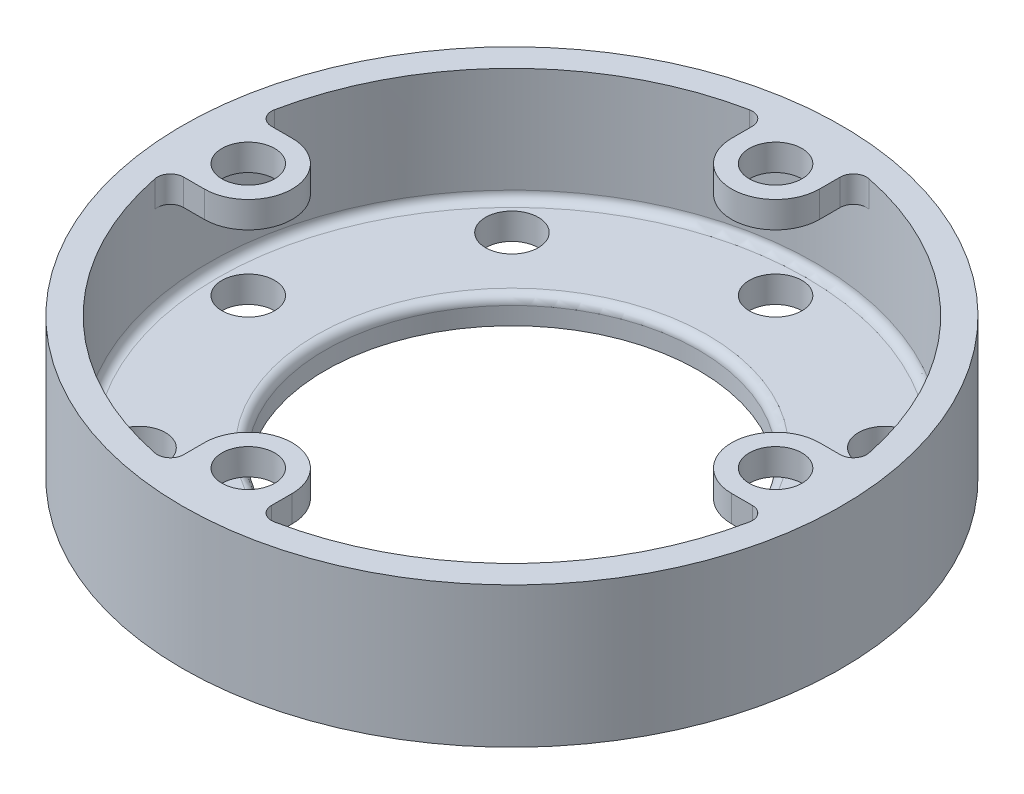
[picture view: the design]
ISO-10303-21;
HEADER;
FILE_DESCRIPTION(('STEP AP214'),'2;1');
FILE_NAME('part.step','',(''),(''),'','','');
FILE_SCHEMA(('AUTOMOTIVE_DESIGN { 1 0 10303 214 1 1 1 1 }'));
ENDSEC;
DATA;
#1=APPLICATION_CONTEXT('core data for automotive mechanical design processes');
#2=APPLICATION_PROTOCOL_DEFINITION('international standard','automotive_design',2000,#1);
#3=PRODUCT_CONTEXT('',#1,'mechanical');
#4=PRODUCT('Part','Part','',(#3));
#5=PRODUCT_RELATED_PRODUCT_CATEGORY('part','',(#4));
#6=PRODUCT_DEFINITION_FORMATION('','',#4);
#7=PRODUCT_DEFINITION_CONTEXT('part definition',#1,'design');
#8=PRODUCT_DEFINITION('design','',#6,#7);
#9=PRODUCT_DEFINITION_SHAPE('','',#8);
#10=(LENGTH_UNIT() NAMED_UNIT(*) SI_UNIT(.MILLI.,.METRE.));
#11=(NAMED_UNIT(*) PLANE_ANGLE_UNIT() SI_UNIT($,.RADIAN.));
#12=(NAMED_UNIT(*) SI_UNIT($,.STERADIAN.) SOLID_ANGLE_UNIT());
#13=UNCERTAINTY_MEASURE_WITH_UNIT(LENGTH_MEASURE(1.E-05),#10,'distance_accuracy_value','');
#14=(GEOMETRIC_REPRESENTATION_CONTEXT(3) GLOBAL_UNCERTAINTY_ASSIGNED_CONTEXT((#13)) GLOBAL_UNIT_ASSIGNED_CONTEXT((#10,
#11,#12)) REPRESENTATION_CONTEXT('',''));
#15=CARTESIAN_POINT('',(0.,0.,0.));
#16=DIRECTION('',(0.,0.,1.));
#17=DIRECTION('',(1.,0.,0.));
#18=AXIS2_PLACEMENT_3D('',#15,#16,#17);
#19=CARTESIAN_POINT('',(0.,32.,0.));
#20=DIRECTION('',(0.,-1.,0.));
#21=DIRECTION('',(0.,0.,-1.));
#22=AXIS2_PLACEMENT_3D('',#19,#20,#21);
#23=CYLINDRICAL_SURFACE('',#22,69.);
#24=CARTESIAN_POINT('',(0.,8.,0.));
#25=DIRECTION('',(0.,1.,0.));
#26=DIRECTION('',(0.,0.,1.));
#27=AXIS2_PLACEMENT_3D('',#24,#25,#26);
#28=CIRCLE('',#27,69.);
#29=CARTESIAN_POINT('',(0.,8.,69.));
#30=VERTEX_POINT('',#29);
#31=EDGE_CURVE('E11',#30,#30,#28,.F.);
#32=ORIENTED_EDGE('',*,*,#31,.T.);
#33=EDGE_LOOP('',(#32));
#34=FACE_BOUND('',#33,.T.);
#35=CARTESIAN_POINT('',(0.,32.,0.));
#36=DIRECTION('',(0.,1.,0.));
#37=DIRECTION('',(0.,0.,1.));
#38=AXIS2_PLACEMENT_3D('',#35,#36,#37);
#39=CIRCLE('',#38,69.);
#40=CARTESIAN_POINT('',(13.5909088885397,32.,67.6482608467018));
#41=VERTEX_POINT('',#40);
#42=CARTESIAN_POINT('',(67.648260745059,32.,13.5909093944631));
#43=VERTEX_POINT('',#42);
#44=EDGE_CURVE('E495',#41,#43,#39,.T.);
#45=ORIENTED_EDGE('',*,*,#44,.T.);
#46=DIRECTION('',(0.,-1.,0.));
#47=VECTOR('',#46,1.);
#48=CARTESIAN_POINT('',(67.648260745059,32.,13.5909093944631));
#49=LINE('',#48,#47);
#50=CARTESIAN_POINT('',(67.648260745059,26.,13.5909093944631));
#51=VERTEX_POINT('',#50);
#52=EDGE_CURVE('E387',#43,#51,#49,.T.);
#53=ORIENTED_EDGE('',*,*,#52,.T.);
#54=CARTESIAN_POINT('',(0.,26.,0.));
#55=DIRECTION('',(0.,1.,0.));
#56=DIRECTION('',(-1.,0.,-4.48724098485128E-09));
#57=AXIS2_PLACEMENT_3D('',#54,#55,#56);
#58=CIRCLE('',#57,69.);
#59=CARTESIAN_POINT('',(67.6482608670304,26.,-13.590908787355));
#60=VERTEX_POINT('',#59);
#61=EDGE_CURVE('E224',#51,#60,#58,.T.);
#62=ORIENTED_EDGE('',*,*,#61,.T.);
#63=DIRECTION('',(0.,-1.,0.));
#64=VECTOR('',#63,1.);
#65=CARTESIAN_POINT('',(67.6482608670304,32.,-13.590908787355));
#66=LINE('',#65,#64);
#67=CARTESIAN_POINT('',(67.6482608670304,32.,-13.590908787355));
#68=VERTEX_POINT('',#67);
#69=EDGE_CURVE('E381',#60,#68,#66,.F.);
#70=ORIENTED_EDGE('',*,*,#69,.T.);
#71=CARTESIAN_POINT('',(13.5909090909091,32.,-67.6482608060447));
#72=VERTEX_POINT('',#71);
#73=EDGE_CURVE('E307',#68,#72,#39,.T.);
#74=ORIENTED_EDGE('',*,*,#73,.T.);
#75=DIRECTION('',(0.,-1.,0.));
#76=VECTOR('',#75,1.);
#77=CARTESIAN_POINT('',(13.5909090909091,32.,-67.6482608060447));
#78=LINE('',#77,#76);
#79=CARTESIAN_POINT('',(13.5909090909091,26.,-67.6482608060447));
#80=VERTEX_POINT('',#79);
#81=EDGE_CURVE('E327',#72,#80,#78,.T.);
#82=ORIENTED_EDGE('',*,*,#81,.T.);
#83=CARTESIAN_POINT('',(0.,26.,0.));
#84=DIRECTION('',(0.,1.,0.));
#85=DIRECTION('',(0.,0.,1.));
#86=AXIS2_PLACEMENT_3D('',#83,#84,#85);
#87=CIRCLE('',#86,69.);
#88=CARTESIAN_POINT('',(-13.5909090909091,26.,-67.6482608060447));
#89=VERTEX_POINT('',#88);
#90=EDGE_CURVE('E282',#80,#89,#87,.T.);
#91=ORIENTED_EDGE('',*,*,#90,.T.);
#92=DIRECTION('',(0.,-1.,0.));
#93=VECTOR('',#92,1.);
#94=CARTESIAN_POINT('',(-13.5909090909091,32.,-67.6482608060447));
#95=LINE('',#94,#93);
#96=CARTESIAN_POINT('',(-13.5909090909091,32.,-67.6482608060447));
#97=VERTEX_POINT('',#96);
#98=EDGE_CURVE('E324',#89,#97,#95,.F.);
#99=ORIENTED_EDGE('',*,*,#98,.T.);
#100=CARTESIAN_POINT('',(-67.6482607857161,32.,-13.5909091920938));
#101=VERTEX_POINT('',#100);
#102=EDGE_CURVE('E309',#97,#101,#39,.T.);
#103=ORIENTED_EDGE('',*,*,#102,.T.);
#104=DIRECTION('',(0.,-1.,0.));
#105=VECTOR('',#104,1.);
#106=CARTESIAN_POINT('',(-67.6482607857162,32.,-13.5909091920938));
#107=LINE('',#106,#105);
#108=CARTESIAN_POINT('',(-67.6482607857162,26.,-13.5909091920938));
#109=VERTEX_POINT('',#108);
#110=EDGE_CURVE('E350',#101,#109,#107,.T.);
#111=ORIENTED_EDGE('',*,*,#110,.T.);
#112=CARTESIAN_POINT('',(0.,26.,0.));
#113=DIRECTION('',(0.,1.,0.));
#114=DIRECTION('',(1.,0.,1.49574714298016E-09));
#115=AXIS2_PLACEMENT_3D('',#112,#113,#114);
#116=CIRCLE('',#115,69.);
#117=CARTESIAN_POINT('',(-67.6482608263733,26.,13.5909089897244));
#118=VERTEX_POINT('',#117);
#119=EDGE_CURVE('E257',#109,#118,#116,.T.);
#120=ORIENTED_EDGE('',*,*,#119,.T.);
#121=DIRECTION('',(0.,-1.,0.));
#122=VECTOR('',#121,1.);
#123=CARTESIAN_POINT('',(-67.6482608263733,32.,13.5909089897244));
#124=LINE('',#123,#122);
#125=CARTESIAN_POINT('',(-67.6482608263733,32.,13.5909089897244));
#126=VERTEX_POINT('',#125);
#127=EDGE_CURVE('E343',#118,#126,#124,.F.);
#128=ORIENTED_EDGE('',*,*,#127,.T.);
#129=CARTESIAN_POINT('',(-13.5909092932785,32.,67.6482607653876));
#130=VERTEX_POINT('',#129);
#131=EDGE_CURVE('E313',#126,#130,#39,.T.);
#132=ORIENTED_EDGE('',*,*,#131,.T.);
#133=DIRECTION('',(0.,-1.,0.));
#134=VECTOR('',#133,1.);
#135=CARTESIAN_POINT('',(-13.5909092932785,32.,67.6482607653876));
#136=LINE('',#135,#134);
#137=CARTESIAN_POINT('',(-13.5909092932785,26.,67.6482607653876));
#138=VERTEX_POINT('',#137);
#139=EDGE_CURVE('E370',#130,#138,#136,.T.);
#140=ORIENTED_EDGE('',*,*,#139,.T.);
#141=CARTESIAN_POINT('',(0.,26.,0.));
#142=DIRECTION('',(0.,1.,0.));
#143=DIRECTION('',(2.99149428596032E-09,0.,-1.));
#144=AXIS2_PLACEMENT_3D('',#141,#142,#143);
#145=CIRCLE('',#144,69.);
#146=CARTESIAN_POINT('',(13.5909088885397,26.,67.6482608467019));
#147=VERTEX_POINT('',#146);
#148=EDGE_CURVE('E232',#138,#147,#145,.T.);
#149=ORIENTED_EDGE('',*,*,#148,.T.);
#150=DIRECTION('',(0.,-1.,0.));
#151=VECTOR('',#150,1.);
#152=CARTESIAN_POINT('',(13.5909088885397,32.,67.6482608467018));
#153=LINE('',#152,#151);
#154=EDGE_CURVE('E364',#147,#41,#153,.F.);
#155=ORIENTED_EDGE('',*,*,#154,.T.);
#156=EDGE_LOOP('',(#45,#53,#62,#70,#74,#82,#91,#99,#103,#111,#120,#128,#132,#140,#149,#155));
#157=FACE_BOUND('',#156,.T.);
#158=ADVANCED_FACE('F39',(#34,#157),#23,.F.);
#159=CARTESIAN_POINT('',(0.,32.,0.));
#160=DIRECTION('',(0.,-1.,0.));
#161=DIRECTION('',(0.,0.,-1.));
#162=AXIS2_PLACEMENT_3D('',#159,#160,#161);
#163=CYLINDRICAL_SURFACE('',#162,75.);
#164=CARTESIAN_POINT('',(0.,32.,0.));
#165=DIRECTION('',(0.,1.,0.));
#166=DIRECTION('',(0.,0.,1.));
#167=AXIS2_PLACEMENT_3D('',#164,#165,#166);
#168=CIRCLE('',#167,75.);
#169=CARTESIAN_POINT('',(0.,32.,75.));
#170=VERTEX_POINT('',#169);
#171=EDGE_CURVE('E314',#170,#170,#168,.T.);
#172=ORIENTED_EDGE('',*,*,#171,.F.);
#173=EDGE_LOOP('',(#172));
#174=FACE_BOUND('',#173,.T.);
#175=CARTESIAN_POINT('',(0.,0.,0.));
#176=DIRECTION('',(0.,1.,0.));
#177=DIRECTION('',(0.,0.,1.));
#178=AXIS2_PLACEMENT_3D('',#175,#176,#177);
#179=CIRCLE('',#178,75.);
#180=CARTESIAN_POINT('',(0.,0.,75.));
#181=VERTEX_POINT('',#180);
#182=EDGE_CURVE('E312',#181,#181,#179,.T.);
#183=ORIENTED_EDGE('',*,*,#182,.T.);
#184=EDGE_LOOP('',(#183));
#185=FACE_BOUND('',#184,.T.);
#186=ADVANCED_FACE('F427',(#174,#185),#163,.T.);
#187=CARTESIAN_POINT('',(0.,32.,0.));
#188=DIRECTION('',(0.,1.,0.));
#189=DIRECTION('',(0.,0.,1.));
#190=AXIS2_PLACEMENT_3D('',#187,#188,#189);
#191=PLANE('',#190);
#192=CARTESIAN_POINT('',(60.,32.,2.69234459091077E-07));
#193=DIRECTION('',(0.,1.,0.));
#194=DIRECTION('',(-1.,0.,-4.48724098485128E-09));
#195=AXIS2_PLACEMENT_3D('',#192,#193,#194);
#196=CIRCLE('',#195,6.);
#197=CARTESIAN_POINT('',(54.,32.,2.42311013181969E-07));
#198=VERTEX_POINT('',#197);
#199=EDGE_CURVE('E656',#198,#198,#196,.T.);
#200=ORIENTED_EDGE('',*,*,#199,.F.);
#201=EDGE_LOOP('',(#200));
#202=FACE_BOUND('',#201,.T.);
#203=CARTESIAN_POINT('',(-1.79489657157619E-07,32.,60.));
#204=DIRECTION('',(0.,1.,0.));
#205=DIRECTION('',(2.99149428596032E-09,0.,-1.));
#206=AXIS2_PLACEMENT_3D('',#203,#204,#205);
#207=CIRCLE('',#206,6.);
#208=CARTESIAN_POINT('',(-1.61540691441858E-07,32.,54.));
#209=VERTEX_POINT('',#208);
#210=EDGE_CURVE('E668',#209,#209,#207,.T.);
#211=ORIENTED_EDGE('',*,*,#210,.F.);
#212=EDGE_LOOP('',(#211));
#213=FACE_BOUND('',#212,.T.);
#214=CARTESIAN_POINT('',(-60.,32.,-8.97448285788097E-08));
#215=DIRECTION('',(0.,1.,0.));
#216=DIRECTION('',(1.,0.,1.49574714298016E-09));
#217=AXIS2_PLACEMENT_3D('',#214,#215,#216);
#218=CIRCLE('',#217,6.);
#219=CARTESIAN_POINT('',(-54.,32.,-8.07703457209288E-08));
#220=VERTEX_POINT('',#219);
#221=EDGE_CURVE('E672',#220,#220,#218,.T.);
#222=ORIENTED_EDGE('',*,*,#221,.F.);
#223=EDGE_LOOP('',(#222));
#224=FACE_BOUND('',#223,.T.);
#225=CARTESIAN_POINT('',(0.,32.,-60.));
#226=DIRECTION('',(0.,1.,0.));
#227=DIRECTION('',(0.,0.,1.));
#228=AXIS2_PLACEMENT_3D('',#225,#226,#227);
#229=CIRCLE('',#228,6.);
#230=CARTESIAN_POINT('',(0.,32.,-54.));
#231=VERTEX_POINT('',#230);
#232=EDGE_CURVE('E276',#231,#231,#229,.T.);
#233=ORIENTED_EDGE('',*,*,#232,.F.);
#234=EDGE_LOOP('',(#233));
#235=FACE_BOUND('',#234,.T.);
#236=ORIENTED_EDGE('',*,*,#102,.F.);
#237=CARTESIAN_POINT('',(-13.,32.,-64.7070320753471));
#238=DIRECTION('',(0.,1.,0.));
#239=DIRECTION('',(0.,0.,1.));
#240=AXIS2_PLACEMENT_3D('',#237,#238,#239);
#241=CIRCLE('',#240,3.);
#242=CARTESIAN_POINT('',(-10.,32.,-64.7070320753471));
#243=VERTEX_POINT('',#242);
#244=EDGE_CURVE('E337',#97,#243,#241,.F.);
#245=ORIENTED_EDGE('',*,*,#244,.T.);
#246=DIRECTION('',(0.,0.,-1.));
#247=VECTOR('',#246,1.);
#248=CARTESIAN_POINT('',(-10.,32.,-60.));
#249=LINE('',#248,#247);
#250=CARTESIAN_POINT('',(-10.,32.,-60.));
#251=VERTEX_POINT('',#250);
#252=EDGE_CURVE('E284',#251,#243,#249,.T.);
#253=ORIENTED_EDGE('',*,*,#252,.F.);
#254=CARTESIAN_POINT('',(0.,32.,-60.));
#255=DIRECTION('',(0.,-1.,0.));
#256=DIRECTION('',(0.,0.,-1.));
#257=AXIS2_PLACEMENT_3D('',#254,#255,#256);
#258=CIRCLE('',#257,10.);
#259=CARTESIAN_POINT('',(10.,32.,-60.));
#260=VERTEX_POINT('',#259);
#261=EDGE_CURVE('E296',#260,#251,#258,.T.);
#262=ORIENTED_EDGE('',*,*,#261,.F.);
#263=DIRECTION('',(0.,0.,1.));
#264=VECTOR('',#263,1.);
#265=CARTESIAN_POINT('',(10.,32.,-68.2715167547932));
#266=LINE('',#265,#264);
#267=CARTESIAN_POINT('',(10.,32.,-64.7070320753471));
#268=VERTEX_POINT('',#267);
#269=EDGE_CURVE('E290',#268,#260,#266,.T.);
#270=ORIENTED_EDGE('',*,*,#269,.F.);
#271=CARTESIAN_POINT('',(13.,32.,-64.7070320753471));
#272=DIRECTION('',(0.,1.,0.));
#273=DIRECTION('',(0.,0.,1.));
#274=AXIS2_PLACEMENT_3D('',#271,#272,#273);
#275=CIRCLE('',#274,3.);
#276=EDGE_CURVE('E333',#268,#72,#275,.F.);
#277=ORIENTED_EDGE('',*,*,#276,.T.);
#278=ORIENTED_EDGE('',*,*,#73,.F.);
#279=CARTESIAN_POINT('',(64.7070321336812,32.,-12.999999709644));
#280=DIRECTION('',(0.,1.,0.));
#281=DIRECTION('',(0.,0.,1.));
#282=AXIS2_PLACEMENT_3D('',#279,#280,#281);
#283=CIRCLE('',#282,3.);
#284=CARTESIAN_POINT('',(64.7070321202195,32.,-9.99999970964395));
#285=VERTEX_POINT('',#284);
#286=EDGE_CURVE('E62',#68,#285,#283,.F.);
#287=ORIENTED_EDGE('',*,*,#286,.T.);
#288=DIRECTION('',(1.,0.,4.48724119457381E-09));
#289=VECTOR('',#288,1.);
#290=CARTESIAN_POINT('',(60.0000000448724,32.,-9.99999973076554));
#291=LINE('',#290,#289);
#292=CARTESIAN_POINT('',(60.0000000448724,32.,-9.99999973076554));
#293=VERTEX_POINT('',#292);
#294=EDGE_CURVE('E226',#293,#285,#291,.T.);
#295=ORIENTED_EDGE('',*,*,#294,.F.);
#296=CARTESIAN_POINT('',(60.,32.,2.69234459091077E-07));
#297=DIRECTION('',(0.,-1.,0.));
#298=DIRECTION('',(1.,0.,4.48724098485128E-09));
#299=AXIS2_PLACEMENT_3D('',#296,#297,#298);
#300=CIRCLE('',#299,10.);
#301=CARTESIAN_POINT('',(59.9999999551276,32.,10.0000002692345));
#302=VERTEX_POINT('',#301);
#303=EDGE_CURVE('E220',#302,#293,#300,.T.);
#304=ORIENTED_EDGE('',*,*,#303,.F.);
#305=DIRECTION('',(-1.,0.,-4.48724077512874E-09));
#306=VECTOR('',#305,1.);
#307=CARTESIAN_POINT('',(68.2715167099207,32.,10.0000003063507));
#308=LINE('',#307,#306);
#309=CARTESIAN_POINT('',(64.7070320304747,32.,10.000000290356));
#310=VERTEX_POINT('',#309);
#311=EDGE_CURVE('E225',#310,#302,#308,.T.);
#312=ORIENTED_EDGE('',*,*,#311,.F.);
#313=CARTESIAN_POINT('',(64.707032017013,32.,13.000000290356));
#314=DIRECTION('',(0.,1.,0.));
#315=DIRECTION('',(0.,0.,1.));
#316=AXIS2_PLACEMENT_3D('',#313,#314,#315);
#317=CIRCLE('',#316,3.);
#318=EDGE_CURVE('E392',#310,#43,#317,.F.);
#319=ORIENTED_EDGE('',*,*,#318,.T.);
#320=ORIENTED_EDGE('',*,*,#44,.F.);
#321=CARTESIAN_POINT('',(12.9999998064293,32.,64.7070321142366));
#322=DIRECTION('',(0.,1.,0.));
#323=DIRECTION('',(0.,0.,1.));
#324=AXIS2_PLACEMENT_3D('',#321,#322,#323);
#325=CIRCLE('',#324,3.);
#326=CARTESIAN_POINT('',(9.99999980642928,32.,64.7070321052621));
#327=VERTEX_POINT('',#326);
#328=EDGE_CURVE('E376',#41,#327,#325,.F.);
#329=ORIENTED_EDGE('',*,*,#328,.T.);
#330=DIRECTION('',(-2.99149449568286E-09,0.,1.));
#331=VECTOR('',#330,1.);
#332=CARTESIAN_POINT('',(9.99999982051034,32.,60.0000000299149));
#333=LINE('',#332,#331);
#334=CARTESIAN_POINT('',(9.99999982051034,32.,60.0000000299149));
#335=VERTEX_POINT('',#334);
#336=EDGE_CURVE('E231',#335,#327,#333,.T.);
#337=ORIENTED_EDGE('',*,*,#336,.F.);
#338=CARTESIAN_POINT('',(-1.79489657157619E-07,32.,60.));
#339=DIRECTION('',(0.,-1.,0.));
#340=DIRECTION('',(-2.99149428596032E-09,0.,1.));
#341=AXIS2_PLACEMENT_3D('',#338,#339,#340);
#342=CIRCLE('',#341,10.);
#343=CARTESIAN_POINT('',(-10.0000001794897,32.,59.999999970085));
#344=VERTEX_POINT('',#343);
#345=EDGE_CURVE('E247',#344,#335,#342,.T.);
#346=ORIENTED_EDGE('',*,*,#345,.F.);
#347=DIRECTION('',(2.99149407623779E-09,0.,-1.));
#348=VECTOR('',#347,1.);
#349=CARTESIAN_POINT('',(-10.0000002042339,32.,68.2715167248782));
#350=LINE('',#349,#348);
#351=CARTESIAN_POINT('',(-10.0000001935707,32.,64.7070320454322));
#352=VERTEX_POINT('',#351);
#353=EDGE_CURVE('E238',#352,#344,#350,.T.);
#354=ORIENTED_EDGE('',*,*,#353,.F.);
#355=CARTESIAN_POINT('',(-13.0000001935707,32.,64.7070320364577));
#356=DIRECTION('',(0.,1.,0.));
#357=DIRECTION('',(0.,0.,1.));
#358=AXIS2_PLACEMENT_3D('',#355,#356,#357);
#359=CIRCLE('',#358,3.);
#360=EDGE_CURVE('E375',#352,#130,#359,.F.);
#361=ORIENTED_EDGE('',*,*,#360,.T.);
#362=ORIENTED_EDGE('',*,*,#131,.F.);
#363=CARTESIAN_POINT('',(-64.7070320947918,32.,12.9999999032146));
#364=DIRECTION('',(0.,1.,0.));
#365=DIRECTION('',(0.,0.,1.));
#366=AXIS2_PLACEMENT_3D('',#363,#364,#365);
#367=CIRCLE('',#366,3.);
#368=CARTESIAN_POINT('',(-64.7070320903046,32.,9.99999990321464));
#369=VERTEX_POINT('',#368);
#370=EDGE_CURVE('E358',#126,#369,#367,.F.);
#371=ORIENTED_EDGE('',*,*,#370,.T.);
#372=DIRECTION('',(-1.,0.,-1.4957473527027E-09));
#373=VECTOR('',#372,1.);
#374=CARTESIAN_POINT('',(-60.0000000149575,32.,9.99999991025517));
#375=LINE('',#374,#373);
#376=CARTESIAN_POINT('',(-60.0000000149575,32.,9.99999991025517));
#377=VERTEX_POINT('',#376);
#378=EDGE_CURVE('E251',#377,#369,#375,.T.);
#379=ORIENTED_EDGE('',*,*,#378,.F.);
#380=CARTESIAN_POINT('',(-60.,32.,-8.97448285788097E-08));
#381=DIRECTION('',(0.,-1.,0.));
#382=DIRECTION('',(-1.,0.,-1.49574714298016E-09));
#383=AXIS2_PLACEMENT_3D('',#380,#381,#382);
#384=CIRCLE('',#383,10.);
#385=CARTESIAN_POINT('',(-59.9999999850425,32.,-10.0000000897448));
#386=VERTEX_POINT('',#385);
#387=EDGE_CURVE('E267',#386,#377,#384,.T.);
#388=ORIENTED_EDGE('',*,*,#387,.F.);
#389=DIRECTION('',(1.,0.,1.49574693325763E-09));
#390=VECTOR('',#389,1.);
#391=CARTESIAN_POINT('',(-68.2715167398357,32.,-10.0000001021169));
#392=LINE('',#391,#390);
#393=CARTESIAN_POINT('',(-64.7070320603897,32.,-10.0000000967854));
#394=VERTEX_POINT('',#393);
#395=EDGE_CURVE('E260',#394,#386,#392,.T.);
#396=ORIENTED_EDGE('',*,*,#395,.F.);
#397=CARTESIAN_POINT('',(-64.7070320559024,32.,-13.0000000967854));
#398=DIRECTION('',(0.,1.,0.));
#399=DIRECTION('',(0.,0.,1.));
#400=AXIS2_PLACEMENT_3D('',#397,#398,#399);
#401=CIRCLE('',#400,3.);
#402=EDGE_CURVE('E351',#394,#101,#401,.F.);
#403=ORIENTED_EDGE('',*,*,#402,.T.);
#404=EDGE_LOOP('',(#236,#245,#253,#262,#270,#277,#278,#287,#295,#304,#312,#319,#320,#329,#337,
#346,#354,#361,#362,#371,#379,#388,#396,#403));
#405=FACE_BOUND('',#404,.T.);
#406=ORIENTED_EDGE('',*,*,#171,.T.);
#407=EDGE_LOOP('',(#406));
#408=FACE_BOUND('',#407,.T.);
#409=ADVANCED_FACE('F424',(#202,#213,#224,#235,#405,#408),#191,.T.);
#410=CARTESIAN_POINT('',(0.,0.,0.));
#411=DIRECTION('',(0.,1.,0.));
#412=DIRECTION('',(0.,0.,1.));
#413=AXIS2_PLACEMENT_3D('',#410,#411,#412);
#414=PLANE('',#413);
#415=CARTESIAN_POINT('',(-42.4264068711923,0.,-42.4264068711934));
#416=DIRECTION('',(0.,1.,0.));
#417=DIRECTION('',(0.707106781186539,0.,0.707106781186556));
#418=AXIS2_PLACEMENT_3D('',#415,#416,#417);
#419=CIRCLE('',#418,6.);
#420=CARTESIAN_POINT('',(-38.1837661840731,0.,-38.183766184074));
#421=VERTEX_POINT('',#420);
#422=EDGE_CURVE('E819',#421,#421,#419,.T.);
#423=ORIENTED_EDGE('',*,*,#422,.T.);
#424=EDGE_LOOP('',(#423));
#425=FACE_BOUND('',#424,.T.);
#426=CARTESIAN_POINT('',(-60.,0.,-6.28466640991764E-13));
#427=DIRECTION('',(0.,1.,0.));
#428=DIRECTION('',(1.,0.,0.));
#429=AXIS2_PLACEMENT_3D('',#426,#427,#428);
#430=CIRCLE('',#429,6.);
#431=CARTESIAN_POINT('',(-54.,0.,-5.65619976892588E-13));
#432=VERTEX_POINT('',#431);
#433=EDGE_CURVE('E823',#432,#432,#430,.T.);
#434=ORIENTED_EDGE('',*,*,#433,.T.);
#435=EDGE_LOOP('',(#434));
#436=FACE_BOUND('',#435,.T.);
#437=CARTESIAN_POINT('',(-42.4264068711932,0.,42.4264068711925));
#438=DIRECTION('',(0.,1.,0.));
#439=DIRECTION('',(0.707106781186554,0.,-0.707106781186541));
#440=AXIS2_PLACEMENT_3D('',#437,#438,#439);
#441=CIRCLE('',#440,6.);
#442=CARTESIAN_POINT('',(-38.1837661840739,0.,38.1837661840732));
#443=VERTEX_POINT('',#442);
#444=EDGE_CURVE('E830',#443,#443,#441,.T.);
#445=ORIENTED_EDGE('',*,*,#444,.T.);
#446=EDGE_LOOP('',(#445));
#447=FACE_BOUND('',#446,.T.);
#448=CARTESIAN_POINT('',(-4.18977760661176E-13,0.,60.));
#449=DIRECTION('',(0.,1.,0.));
#450=DIRECTION('',(0.,0.,-1.));
#451=AXIS2_PLACEMENT_3D('',#448,#449,#450);
#452=CIRCLE('',#451,6.);
#453=CARTESIAN_POINT('',(-3.77079984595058E-13,0.,54.));
#454=VERTEX_POINT('',#453);
#455=EDGE_CURVE('E831',#454,#454,#452,.T.);
#456=ORIENTED_EDGE('',*,*,#455,.T.);
#457=EDGE_LOOP('',(#456));
#458=FACE_BOUND('',#457,.T.);
#459=CARTESIAN_POINT('',(42.4264068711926,0.,42.4264068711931));
#460=DIRECTION('',(0.,1.,0.));
#461=DIRECTION('',(-0.707106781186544,0.,-0.707106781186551));
#462=AXIS2_PLACEMENT_3D('',#459,#460,#461);
#463=CIRCLE('',#462,6.);
#464=CARTESIAN_POINT('',(38.1837661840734,0.,38.1837661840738));
#465=VERTEX_POINT('',#464);
#466=EDGE_CURVE('E834',#465,#465,#463,.T.);
#467=ORIENTED_EDGE('',*,*,#466,.T.);
#468=EDGE_LOOP('',(#467));
#469=FACE_BOUND('',#468,.T.);
#470=CARTESIAN_POINT('',(60.,0.,2.09488880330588E-13));
#471=DIRECTION('',(0.,1.,0.));
#472=DIRECTION('',(-1.,0.,0.));
#473=AXIS2_PLACEMENT_3D('',#470,#471,#472);
#474=CIRCLE('',#473,6.);
#475=CARTESIAN_POINT('',(54.,0.,1.88539992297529E-13));
#476=VERTEX_POINT('',#475);
#477=EDGE_CURVE('E836',#476,#476,#474,.T.);
#478=ORIENTED_EDGE('',*,*,#477,.T.);
#479=EDGE_LOOP('',(#478));
#480=FACE_BOUND('',#479,.T.);
#481=CARTESIAN_POINT('',(42.4264068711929,0.,-42.4264068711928));
#482=DIRECTION('',(0.,1.,0.));
#483=DIRECTION('',(-0.707106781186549,0.,0.707106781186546));
#484=AXIS2_PLACEMENT_3D('',#481,#482,#483);
#485=CIRCLE('',#484,6.);
#486=CARTESIAN_POINT('',(38.1837661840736,0.,-38.1837661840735));
#487=VERTEX_POINT('',#486);
#488=EDGE_CURVE('E653',#487,#487,#485,.T.);
#489=ORIENTED_EDGE('',*,*,#488,.T.);
#490=EDGE_LOOP('',(#489));
#491=FACE_BOUND('',#490,.T.);
#492=CARTESIAN_POINT('',(0.,0.,-60.));
#493=DIRECTION('',(0.,1.,0.));
#494=DIRECTION('',(0.,0.,1.));
#495=AXIS2_PLACEMENT_3D('',#492,#493,#494);
#496=CIRCLE('',#495,6.);
#497=CARTESIAN_POINT('',(0.,0.,-54.));
#498=VERTEX_POINT('',#497);
#499=EDGE_CURVE('E651',#498,#498,#496,.T.);
#500=ORIENTED_EDGE('',*,*,#499,.T.);
#501=EDGE_LOOP('',(#500));
#502=FACE_BOUND('',#501,.T.);
#503=CARTESIAN_POINT('',(0.,0.,0.));
#504=DIRECTION('',(0.,1.,0.));
#505=DIRECTION('',(0.,0.,1.));
#506=AXIS2_PLACEMENT_3D('',#503,#504,#505);
#507=CIRCLE('',#506,42.5);
#508=CARTESIAN_POINT('',(0.,0.,42.5));
#509=VERTEX_POINT('',#508);
#510=EDGE_CURVE('E302',#509,#509,#507,.T.);
#511=ORIENTED_EDGE('',*,*,#510,.T.);
#512=EDGE_LOOP('',(#511));
#513=FACE_BOUND('',#512,.T.);
#514=ORIENTED_EDGE('',*,*,#182,.F.);
#515=EDGE_LOOP('',(#514));
#516=FACE_BOUND('',#515,.T.);
#517=ADVANCED_FACE('F422',(#425,#436,#447,#458,#469,#480,#491,#502,#513,#516),#414,.F.);
#518=CARTESIAN_POINT('',(0.,6.,0.));
#519=DIRECTION('',(0.,1.,0.));
#520=DIRECTION('',(0.,0.,1.));
#521=AXIS2_PLACEMENT_3D('',#518,#519,#520);
#522=PLANE('',#521);
#523=CARTESIAN_POINT('',(0.,6.,0.));
#524=DIRECTION('',(0.,1.,0.));
#525=DIRECTION('',(0.,0.,1.));
#526=AXIS2_PLACEMENT_3D('',#523,#524,#525);
#527=CIRCLE('',#526,44.5);
#528=CARTESIAN_POINT('',(0.,6.,44.5));
#529=VERTEX_POINT('',#528);
#530=EDGE_CURVE('E50',#529,#529,#527,.F.);
#531=ORIENTED_EDGE('',*,*,#530,.T.);
#532=EDGE_LOOP('',(#531));
#533=FACE_BOUND('',#532,.T.);
#534=CARTESIAN_POINT('',(0.,6.,0.));
#535=DIRECTION('',(0.,1.,0.));
#536=DIRECTION('',(0.,0.,1.));
#537=AXIS2_PLACEMENT_3D('',#534,#535,#536);
#538=CIRCLE('',#537,67.);
#539=CARTESIAN_POINT('',(0.,6.,67.));
#540=VERTEX_POINT('',#539);
#541=EDGE_CURVE('E402',#540,#540,#538,.T.);
#542=ORIENTED_EDGE('',*,*,#541,.T.);
#543=EDGE_LOOP('',(#542));
#544=FACE_BOUND('',#543,.T.);
#545=CARTESIAN_POINT('',(-42.4264068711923,6.,-42.4264068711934));
#546=DIRECTION('',(0.,1.,0.));
#547=DIRECTION('',(0.707106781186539,0.,0.707106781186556));
#548=AXIS2_PLACEMENT_3D('',#545,#546,#547);
#549=CIRCLE('',#548,6.);
#550=CARTESIAN_POINT('',(-38.1837661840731,6.,-38.183766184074));
#551=VERTEX_POINT('',#550);
#552=EDGE_CURVE('E622',#551,#551,#549,.T.);
#553=ORIENTED_EDGE('',*,*,#552,.F.);
#554=EDGE_LOOP('',(#553));
#555=FACE_BOUND('',#554,.T.);
#556=CARTESIAN_POINT('',(-60.,6.,-6.28466640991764E-13));
#557=DIRECTION('',(0.,1.,0.));
#558=DIRECTION('',(1.,0.,0.));
#559=AXIS2_PLACEMENT_3D('',#556,#557,#558);
#560=CIRCLE('',#559,6.);
#561=CARTESIAN_POINT('',(-54.,6.,-5.65619976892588E-13));
#562=VERTEX_POINT('',#561);
#563=EDGE_CURVE('E627',#562,#562,#560,.T.);
#564=ORIENTED_EDGE('',*,*,#563,.F.);
#565=EDGE_LOOP('',(#564));
#566=FACE_BOUND('',#565,.T.);
#567=CARTESIAN_POINT('',(-42.4264068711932,6.,42.4264068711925));
#568=DIRECTION('',(0.,1.,0.));
#569=DIRECTION('',(0.707106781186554,0.,-0.707106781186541));
#570=AXIS2_PLACEMENT_3D('',#567,#568,#569);
#571=CIRCLE('',#570,6.);
#572=CARTESIAN_POINT('',(-38.1837661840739,6.,38.1837661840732));
#573=VERTEX_POINT('',#572);
#574=EDGE_CURVE('E633',#573,#573,#571,.T.);
#575=ORIENTED_EDGE('',*,*,#574,.F.);
#576=EDGE_LOOP('',(#575));
#577=FACE_BOUND('',#576,.T.);
#578=CARTESIAN_POINT('',(-4.18977760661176E-13,6.,60.));
#579=DIRECTION('',(0.,1.,0.));
#580=DIRECTION('',(0.,0.,-1.));
#581=AXIS2_PLACEMENT_3D('',#578,#579,#580);
#582=CIRCLE('',#581,6.);
#583=CARTESIAN_POINT('',(-3.77079984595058E-13,6.,54.));
#584=VERTEX_POINT('',#583);
#585=EDGE_CURVE('E640',#584,#584,#582,.T.);
#586=ORIENTED_EDGE('',*,*,#585,.F.);
#587=EDGE_LOOP('',(#586));
#588=FACE_BOUND('',#587,.T.);
#589=CARTESIAN_POINT('',(42.4264068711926,6.,42.4264068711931));
#590=DIRECTION('',(0.,1.,0.));
#591=DIRECTION('',(-0.707106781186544,0.,-0.707106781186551));
#592=AXIS2_PLACEMENT_3D('',#589,#590,#591);
#593=CIRCLE('',#592,6.);
#594=CARTESIAN_POINT('',(38.1837661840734,6.,38.1837661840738));
#595=VERTEX_POINT('',#594);
#596=EDGE_CURVE('E642',#595,#595,#593,.T.);
#597=ORIENTED_EDGE('',*,*,#596,.F.);
#598=EDGE_LOOP('',(#597));
#599=FACE_BOUND('',#598,.T.);
#600=CARTESIAN_POINT('',(60.,6.,2.09488880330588E-13));
#601=DIRECTION('',(0.,1.,0.));
#602=DIRECTION('',(-1.,0.,0.));
#603=AXIS2_PLACEMENT_3D('',#600,#601,#602);
#604=CIRCLE('',#603,6.);
#605=CARTESIAN_POINT('',(54.,6.,1.88539992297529E-13));
#606=VERTEX_POINT('',#605);
#607=EDGE_CURVE('E643',#606,#606,#604,.T.);
#608=ORIENTED_EDGE('',*,*,#607,.F.);
#609=EDGE_LOOP('',(#608));
#610=FACE_BOUND('',#609,.T.);
#611=CARTESIAN_POINT('',(42.4264068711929,6.,-42.4264068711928));
#612=DIRECTION('',(0.,1.,0.));
#613=DIRECTION('',(-0.707106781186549,0.,0.707106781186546));
#614=AXIS2_PLACEMENT_3D('',#611,#612,#613);
#615=CIRCLE('',#614,6.);
#616=CARTESIAN_POINT('',(38.1837661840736,6.,-38.1837661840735));
#617=VERTEX_POINT('',#616);
#618=EDGE_CURVE('E648',#617,#617,#615,.T.);
#619=ORIENTED_EDGE('',*,*,#618,.F.);
#620=EDGE_LOOP('',(#619));
#621=FACE_BOUND('',#620,.T.);
#622=CARTESIAN_POINT('',(0.,6.,-60.));
#623=DIRECTION('',(0.,1.,0.));
#624=DIRECTION('',(0.,0.,1.));
#625=AXIS2_PLACEMENT_3D('',#622,#623,#624);
#626=CIRCLE('',#625,6.);
#627=CARTESIAN_POINT('',(0.,6.,-54.));
#628=VERTEX_POINT('',#627);
#629=EDGE_CURVE('E654',#628,#628,#626,.T.);
#630=ORIENTED_EDGE('',*,*,#629,.F.);
#631=EDGE_LOOP('',(#630));
#632=FACE_BOUND('',#631,.T.);
#633=ADVANCED_FACE('F406',(#533,#544,#555,#566,#577,#588,#599,#610,#621,#632),#522,.T.);
#634=CARTESIAN_POINT('',(0.,0.,0.));
#635=DIRECTION('',(0.,1.,0.));
#636=DIRECTION('',(0.,0.,1.));
#637=AXIS2_PLACEMENT_3D('',#634,#635,#636);
#638=CYLINDRICAL_SURFACE('',#637,42.5);
#639=CARTESIAN_POINT('',(0.,4.,0.));
#640=DIRECTION('',(0.,1.,0.));
#641=DIRECTION('',(0.,0.,1.));
#642=AXIS2_PLACEMENT_3D('',#639,#640,#641);
#643=CIRCLE('',#642,42.5);
#644=CARTESIAN_POINT('',(0.,4.,42.5));
#645=VERTEX_POINT('',#644);
#646=EDGE_CURVE('E396',#645,#645,#643,.T.);
#647=ORIENTED_EDGE('',*,*,#646,.T.);
#648=EDGE_LOOP('',(#647));
#649=FACE_BOUND('',#648,.T.);
#650=ORIENTED_EDGE('',*,*,#510,.F.);
#651=EDGE_LOOP('',(#650));
#652=FACE_BOUND('',#651,.T.);
#653=ADVANCED_FACE('F412',(#649,#652),#638,.F.);
#654=CARTESIAN_POINT('',(10.,26.,-68.2715167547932));
#655=DIRECTION('',(-1.,0.,0.));
#656=DIRECTION('',(0.,0.,1.));
#657=AXIS2_PLACEMENT_3D('',#654,#655,#656);
#658=PLANE('',#657);
#659=DIRECTION('',(0.,0.,1.));
#660=VECTOR('',#659,1.);
#661=CARTESIAN_POINT('',(10.,26.,-68.2715167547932));
#662=LINE('',#661,#660);
#663=CARTESIAN_POINT('',(10.,26.,-64.7070320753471));
#664=VERTEX_POINT('',#663);
#665=CARTESIAN_POINT('',(10.,26.,-60.));
#666=VERTEX_POINT('',#665);
#667=EDGE_CURVE('E291',#664,#666,#662,.T.);
#668=ORIENTED_EDGE('',*,*,#667,.F.);
#669=DIRECTION('',(0.,-1.,0.));
#670=VECTOR('',#669,1.);
#671=CARTESIAN_POINT('',(10.,26.,-64.7070320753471));
#672=LINE('',#671,#670);
#673=EDGE_CURVE('E319',#664,#268,#672,.F.);
#674=ORIENTED_EDGE('',*,*,#673,.T.);
#675=ORIENTED_EDGE('',*,*,#269,.T.);
#676=DIRECTION('',(0.,1.,0.));
#677=VECTOR('',#676,1.);
#678=CARTESIAN_POINT('',(10.,26.,-60.));
#679=LINE('',#678,#677);
#680=EDGE_CURVE('E301',#666,#260,#679,.T.);
#681=ORIENTED_EDGE('',*,*,#680,.F.);
#682=EDGE_LOOP('',(#668,#674,#675,#681));
#683=FACE_BOUND('',#682,.T.);
#684=ADVANCED_FACE('F420',(#683),#658,.F.);
#685=CARTESIAN_POINT('',(0.,26.,-60.));
#686=DIRECTION('',(0.,1.,0.));
#687=DIRECTION('',(0.,0.,1.));
#688=AXIS2_PLACEMENT_3D('',#685,#686,#687);
#689=CYLINDRICAL_SURFACE('',#688,10.);
#690=ORIENTED_EDGE('',*,*,#261,.T.);
#691=DIRECTION('',(0.,1.,0.));
#692=VECTOR('',#691,1.);
#693=CARTESIAN_POINT('',(-10.,26.,-60.));
#694=LINE('',#693,#692);
#695=CARTESIAN_POINT('',(-10.,26.,-60.));
#696=VERTEX_POINT('',#695);
#697=EDGE_CURVE('E294',#696,#251,#694,.T.);
#698=ORIENTED_EDGE('',*,*,#697,.F.);
#699=CARTESIAN_POINT('',(0.,26.,-60.));
#700=DIRECTION('',(0.,-1.,0.));
#701=DIRECTION('',(0.,0.,-1.));
#702=AXIS2_PLACEMENT_3D('',#699,#700,#701);
#703=CIRCLE('',#702,10.);
#704=EDGE_CURVE('E293',#666,#696,#703,.T.);
#705=ORIENTED_EDGE('',*,*,#704,.F.);
#706=ORIENTED_EDGE('',*,*,#680,.T.);
#707=EDGE_LOOP('',(#690,#698,#705,#706));
#708=FACE_BOUND('',#707,.T.);
#709=ADVANCED_FACE('F511',(#708),#689,.T.);
#710=CARTESIAN_POINT('',(-10.,26.,-60.));
#711=DIRECTION('',(1.,0.,0.));
#712=DIRECTION('',(0.,0.,-1.));
#713=AXIS2_PLACEMENT_3D('',#710,#711,#712);
#714=PLANE('',#713);
#715=ORIENTED_EDGE('',*,*,#252,.T.);
#716=DIRECTION('',(0.,-1.,0.));
#717=VECTOR('',#716,1.);
#718=CARTESIAN_POINT('',(-10.,26.,-64.7070320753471));
#719=LINE('',#718,#717);
#720=CARTESIAN_POINT('',(-10.,26.,-64.7070320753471));
#721=VERTEX_POINT('',#720);
#722=EDGE_CURVE('E326',#243,#721,#719,.T.);
#723=ORIENTED_EDGE('',*,*,#722,.T.);
#724=DIRECTION('',(0.,0.,-1.));
#725=VECTOR('',#724,1.);
#726=CARTESIAN_POINT('',(-10.,26.,-60.));
#727=LINE('',#726,#725);
#728=EDGE_CURVE('E286',#696,#721,#727,.T.);
#729=ORIENTED_EDGE('',*,*,#728,.F.);
#730=ORIENTED_EDGE('',*,*,#697,.T.);
#731=EDGE_LOOP('',(#715,#723,#729,#730));
#732=FACE_BOUND('',#731,.T.);
#733=ADVANCED_FACE('F587',(#732),#714,.F.);
#734=CARTESIAN_POINT('',(0.,26.,0.));
#735=DIRECTION('',(0.,1.,0.));
#736=DIRECTION('',(0.,0.,1.));
#737=AXIS2_PLACEMENT_3D('',#734,#735,#736);
#738=PLANE('',#737);
#739=CARTESIAN_POINT('',(0.,26.,-60.));
#740=DIRECTION('',(0.,1.,0.));
#741=DIRECTION('',(0.,0.,1.));
#742=AXIS2_PLACEMENT_3D('',#739,#740,#741);
#743=CIRCLE('',#742,6.);
#744=CARTESIAN_POINT('',(0.,26.,-54.));
#745=VERTEX_POINT('',#744);
#746=EDGE_CURVE('E283',#745,#745,#743,.F.);
#747=ORIENTED_EDGE('',*,*,#746,.F.);
#748=EDGE_LOOP('',(#747));
#749=FACE_BOUND('',#748,.T.);
#750=ORIENTED_EDGE('',*,*,#90,.F.);
#751=CARTESIAN_POINT('',(13.,26.,-64.7070320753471));
#752=DIRECTION('',(0.,1.,0.));
#753=DIRECTION('',(0.,0.,1.));
#754=AXIS2_PLACEMENT_3D('',#751,#752,#753);
#755=CIRCLE('',#754,3.);
#756=EDGE_CURVE('E334',#80,#664,#755,.T.);
#757=ORIENTED_EDGE('',*,*,#756,.T.);
#758=ORIENTED_EDGE('',*,*,#667,.T.);
#759=ORIENTED_EDGE('',*,*,#704,.T.);
#760=ORIENTED_EDGE('',*,*,#728,.T.);
#761=CARTESIAN_POINT('',(-13.,26.,-64.7070320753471));
#762=DIRECTION('',(0.,1.,0.));
#763=DIRECTION('',(0.,0.,1.));
#764=AXIS2_PLACEMENT_3D('',#761,#762,#763);
#765=CIRCLE('',#764,3.);
#766=EDGE_CURVE('E336',#721,#89,#765,.T.);
#767=ORIENTED_EDGE('',*,*,#766,.T.);
#768=EDGE_LOOP('',(#750,#757,#758,#759,#760,#767));
#769=FACE_BOUND('',#768,.T.);
#770=ADVANCED_FACE('F507',(#749,#769),#738,.F.);
#771=CARTESIAN_POINT('',(0.,-0.001000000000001,-60.));
#772=DIRECTION('',(0.,1.,0.));
#773=DIRECTION('',(0.,0.,1.));
#774=AXIS2_PLACEMENT_3D('',#771,#772,#773);
#775=CYLINDRICAL_SURFACE('',#774,6.);
#776=ORIENTED_EDGE('',*,*,#232,.T.);
#777=EDGE_LOOP('',(#776));
#778=FACE_BOUND('',#777,.T.);
#779=ORIENTED_EDGE('',*,*,#746,.T.);
#780=EDGE_LOOP('',(#779));
#781=FACE_BOUND('',#780,.T.);
#782=ADVANCED_FACE('F446',(#778,#781),#775,.F.);
#783=CARTESIAN_POINT('',(13.,32.,-64.7070320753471));
#784=DIRECTION('',(0.,-1.,0.));
#785=DIRECTION('',(0.,0.,-1.));
#786=AXIS2_PLACEMENT_3D('',#783,#784,#785);
#787=CYLINDRICAL_SURFACE('',#786,3.);
#788=ORIENTED_EDGE('',*,*,#756,.F.);
#789=ORIENTED_EDGE('',*,*,#81,.F.);
#790=ORIENTED_EDGE('',*,*,#276,.F.);
#791=ORIENTED_EDGE('',*,*,#673,.F.);
#792=EDGE_LOOP('',(#788,#789,#790,#791));
#793=FACE_BOUND('',#792,.T.);
#794=ADVANCED_FACE('F444',(#793),#787,.F.);
#795=CARTESIAN_POINT('',(-13.,32.,-64.7070320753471));
#796=DIRECTION('',(0.,-1.,0.));
#797=DIRECTION('',(0.,0.,-1.));
#798=AXIS2_PLACEMENT_3D('',#795,#796,#797);
#799=CYLINDRICAL_SURFACE('',#798,3.);
#800=ORIENTED_EDGE('',*,*,#766,.F.);
#801=ORIENTED_EDGE('',*,*,#722,.F.);
#802=ORIENTED_EDGE('',*,*,#244,.F.);
#803=ORIENTED_EDGE('',*,*,#98,.F.);
#804=EDGE_LOOP('',(#800,#801,#802,#803));
#805=FACE_BOUND('',#804,.T.);
#806=ADVANCED_FACE('F449',(#805),#799,.F.);
#807=CARTESIAN_POINT('',(-68.2715167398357,26.,-10.0000001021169));
#808=DIRECTION('',(-1.49574693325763E-09,0.,1.));
#809=DIRECTION('',(1.,0.,1.49574693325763E-09));
#810=AXIS2_PLACEMENT_3D('',#807,#808,#809);
#811=PLANE('',#810);
#812=DIRECTION('',(1.,0.,1.49574693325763E-09));
#813=VECTOR('',#812,1.);
#814=CARTESIAN_POINT('',(-68.2715167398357,26.,-10.0000001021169));
#815=LINE('',#814,#813);
#816=CARTESIAN_POINT('',(-64.7070320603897,26.,-10.0000000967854));
#817=VERTEX_POINT('',#816);
#818=CARTESIAN_POINT('',(-59.9999999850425,26.,-10.0000000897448));
#819=VERTEX_POINT('',#818);
#820=EDGE_CURVE('E263',#817,#819,#815,.T.);
#821=ORIENTED_EDGE('',*,*,#820,.F.);
#822=DIRECTION('',(0.,-1.,0.));
#823=VECTOR('',#822,1.);
#824=CARTESIAN_POINT('',(-64.7070320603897,26.,-10.0000000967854));
#825=LINE('',#824,#823);
#826=EDGE_CURVE('E341',#817,#394,#825,.F.);
#827=ORIENTED_EDGE('',*,*,#826,.T.);
#828=ORIENTED_EDGE('',*,*,#395,.T.);
#829=DIRECTION('',(0.,1.,0.));
#830=VECTOR('',#829,1.);
#831=CARTESIAN_POINT('',(-59.9999999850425,26.,-10.0000000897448));
#832=LINE('',#831,#830);
#833=EDGE_CURVE('E271',#819,#386,#832,.T.);
#834=ORIENTED_EDGE('',*,*,#833,.F.);
#835=EDGE_LOOP('',(#821,#827,#828,#834));
#836=FACE_BOUND('',#835,.T.);
#837=ADVANCED_FACE('F454',(#836),#811,.F.);
#838=CARTESIAN_POINT('',(-60.,26.,-8.97448285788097E-08));
#839=DIRECTION('',(0.,1.,0.));
#840=DIRECTION('',(0.,0.,1.));
#841=AXIS2_PLACEMENT_3D('',#838,#839,#840);
#842=CYLINDRICAL_SURFACE('',#841,10.);
#843=ORIENTED_EDGE('',*,*,#387,.T.);
#844=DIRECTION('',(0.,1.,0.));
#845=VECTOR('',#844,1.);
#846=CARTESIAN_POINT('',(-60.0000000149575,26.,9.99999991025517));
#847=LINE('',#846,#845);
#848=CARTESIAN_POINT('',(-60.0000000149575,26.,9.99999991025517));
#849=VERTEX_POINT('',#848);
#850=EDGE_CURVE('E270',#849,#377,#847,.T.);
#851=ORIENTED_EDGE('',*,*,#850,.F.);
#852=CARTESIAN_POINT('',(-60.,26.,-8.97448285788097E-08));
#853=DIRECTION('',(0.,-1.,0.));
#854=DIRECTION('',(-1.,0.,-1.49574714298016E-09));
#855=AXIS2_PLACEMENT_3D('',#852,#853,#854);
#856=CIRCLE('',#855,10.);
#857=EDGE_CURVE('E265',#819,#849,#856,.T.);
#858=ORIENTED_EDGE('',*,*,#857,.F.);
#859=ORIENTED_EDGE('',*,*,#833,.T.);
#860=EDGE_LOOP('',(#843,#851,#858,#859));
#861=FACE_BOUND('',#860,.T.);
#862=ADVANCED_FACE('F573',(#861),#842,.T.);
#863=CARTESIAN_POINT('',(-60.0000000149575,26.,9.99999991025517));
#864=DIRECTION('',(1.4957473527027E-09,0.,-1.));
#865=DIRECTION('',(-1.,0.,-1.4957473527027E-09));
#866=AXIS2_PLACEMENT_3D('',#863,#864,#865);
#867=PLANE('',#866);
#868=ORIENTED_EDGE('',*,*,#378,.T.);
#869=DIRECTION('',(0.,-1.,0.));
#870=VECTOR('',#869,1.);
#871=CARTESIAN_POINT('',(-64.7070320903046,26.,9.99999990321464));
#872=LINE('',#871,#870);
#873=CARTESIAN_POINT('',(-64.7070320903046,26.,9.99999990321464));
#874=VERTEX_POINT('',#873);
#875=EDGE_CURVE('E347',#369,#874,#872,.T.);
#876=ORIENTED_EDGE('',*,*,#875,.T.);
#877=DIRECTION('',(-1.,0.,-1.4957473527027E-09));
#878=VECTOR('',#877,1.);
#879=CARTESIAN_POINT('',(-60.0000000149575,26.,9.99999991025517));
#880=LINE('',#879,#878);
#881=EDGE_CURVE('E258',#849,#874,#880,.T.);
#882=ORIENTED_EDGE('',*,*,#881,.F.);
#883=ORIENTED_EDGE('',*,*,#850,.T.);
#884=EDGE_LOOP('',(#868,#876,#882,#883));
#885=FACE_BOUND('',#884,.T.);
#886=ADVANCED_FACE('F569',(#885),#867,.F.);
#887=CARTESIAN_POINT('',(0.,26.,0.));
#888=DIRECTION('',(0.,1.,0.));
#889=DIRECTION('',(1.,0.,1.49574714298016E-09));
#890=AXIS2_PLACEMENT_3D('',#887,#888,#889);
#891=PLANE('',#890);
#892=CARTESIAN_POINT('',(-60.,26.,-8.97448285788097E-08));
#893=DIRECTION('',(0.,1.,0.));
#894=DIRECTION('',(0.,0.,1.));
#895=AXIS2_PLACEMENT_3D('',#892,#893,#894);
#896=CIRCLE('',#895,6.);
#897=CARTESIAN_POINT('',(-60.,26.,5.99999991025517));
#898=VERTEX_POINT('',#897);
#899=EDGE_CURVE('E229',#898,#898,#896,.F.);
#900=ORIENTED_EDGE('',*,*,#899,.F.);
#901=EDGE_LOOP('',(#900));
#902=FACE_BOUND('',#901,.T.);
#903=ORIENTED_EDGE('',*,*,#119,.F.);
#904=CARTESIAN_POINT('',(-64.7070320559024,26.,-13.0000000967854));
#905=DIRECTION('',(0.,1.,0.));
#906=DIRECTION('',(0.,0.,1.));
#907=AXIS2_PLACEMENT_3D('',#904,#905,#906);
#908=CIRCLE('',#907,3.);
#909=EDGE_CURVE('E353',#109,#817,#908,.T.);
#910=ORIENTED_EDGE('',*,*,#909,.T.);
#911=ORIENTED_EDGE('',*,*,#820,.T.);
#912=ORIENTED_EDGE('',*,*,#857,.T.);
#913=ORIENTED_EDGE('',*,*,#881,.T.);
#914=CARTESIAN_POINT('',(-64.7070320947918,26.,12.9999999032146));
#915=DIRECTION('',(0.,1.,0.));
#916=DIRECTION('',(0.,0.,1.));
#917=AXIS2_PLACEMENT_3D('',#914,#915,#916);
#918=CIRCLE('',#917,3.);
#919=EDGE_CURVE('E356',#874,#118,#918,.T.);
#920=ORIENTED_EDGE('',*,*,#919,.T.);
#921=EDGE_LOOP('',(#903,#910,#911,#912,#913,#920));
#922=FACE_BOUND('',#921,.T.);
#923=ADVANCED_FACE('F532',(#902,#922),#891,.F.);
#924=CARTESIAN_POINT('',(-10.0000002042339,26.,68.2715167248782));
#925=DIRECTION('',(1.,0.,2.99149407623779E-09));
#926=DIRECTION('',(2.99149407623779E-09,0.,-1.));
#927=AXIS2_PLACEMENT_3D('',#924,#925,#926);
#928=PLANE('',#927);
#929=DIRECTION('',(2.99149407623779E-09,0.,-1.));
#930=VECTOR('',#929,1.);
#931=CARTESIAN_POINT('',(-10.0000002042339,26.,68.2715167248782));
#932=LINE('',#931,#930);
#933=CARTESIAN_POINT('',(-10.0000001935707,26.,64.7070320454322));
#934=VERTEX_POINT('',#933);
#935=CARTESIAN_POINT('',(-10.0000001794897,26.,59.999999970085));
#936=VERTEX_POINT('',#935);
#937=EDGE_CURVE('E243',#934,#936,#932,.T.);
#938=ORIENTED_EDGE('',*,*,#937,.F.);
#939=DIRECTION('',(0.,-1.,0.));
#940=VECTOR('',#939,1.);
#941=CARTESIAN_POINT('',(-10.0000001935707,26.,64.7070320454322));
#942=LINE('',#941,#940);
#943=EDGE_CURVE('E363',#934,#352,#942,.F.);
#944=ORIENTED_EDGE('',*,*,#943,.T.);
#945=ORIENTED_EDGE('',*,*,#353,.T.);
#946=DIRECTION('',(0.,1.,0.));
#947=VECTOR('',#946,1.);
#948=CARTESIAN_POINT('',(-10.0000001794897,26.,59.999999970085));
#949=LINE('',#948,#947);
#950=EDGE_CURVE('E252',#936,#344,#949,.T.);
#951=ORIENTED_EDGE('',*,*,#950,.F.);
#952=EDGE_LOOP('',(#938,#944,#945,#951));
#953=FACE_BOUND('',#952,.T.);
#954=ADVANCED_FACE('F544',(#953),#928,.F.);
#955=CARTESIAN_POINT('',(-1.79489657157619E-07,26.,60.));
#956=DIRECTION('',(0.,1.,0.));
#957=DIRECTION('',(0.,0.,1.));
#958=AXIS2_PLACEMENT_3D('',#955,#956,#957);
#959=CYLINDRICAL_SURFACE('',#958,10.);
#960=ORIENTED_EDGE('',*,*,#345,.T.);
#961=DIRECTION('',(0.,1.,0.));
#962=VECTOR('',#961,1.);
#963=CARTESIAN_POINT('',(9.99999982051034,26.,60.0000000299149));
#964=LINE('',#963,#962);
#965=CARTESIAN_POINT('',(9.99999982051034,26.,60.0000000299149));
#966=VERTEX_POINT('',#965);
#967=EDGE_CURVE('E244',#966,#335,#964,.T.);
#968=ORIENTED_EDGE('',*,*,#967,.F.);
#969=CARTESIAN_POINT('',(-1.79489657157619E-07,26.,60.));
#970=DIRECTION('',(0.,-1.,0.));
#971=DIRECTION('',(-2.99149428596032E-09,0.,1.));
#972=AXIS2_PLACEMENT_3D('',#969,#970,#971);
#973=CIRCLE('',#972,10.);
#974=EDGE_CURVE('E241',#936,#966,#973,.T.);
#975=ORIENTED_EDGE('',*,*,#974,.F.);
#976=ORIENTED_EDGE('',*,*,#950,.T.);
#977=EDGE_LOOP('',(#960,#968,#975,#976));
#978=FACE_BOUND('',#977,.T.);
#979=ADVANCED_FACE('F560',(#978),#959,.T.);
#980=CARTESIAN_POINT('',(9.99999982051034,26.,60.0000000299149));
#981=DIRECTION('',(-1.,0.,-2.99149449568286E-09));
#982=DIRECTION('',(-2.99149449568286E-09,0.,1.));
#983=AXIS2_PLACEMENT_3D('',#980,#981,#982);
#984=PLANE('',#983);
#985=ORIENTED_EDGE('',*,*,#336,.T.);
#986=DIRECTION('',(0.,-1.,0.));
#987=VECTOR('',#986,1.);
#988=CARTESIAN_POINT('',(9.99999980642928,26.,64.7070321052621));
#989=LINE('',#988,#987);
#990=CARTESIAN_POINT('',(9.99999980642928,26.,64.7070321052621));
#991=VERTEX_POINT('',#990);
#992=EDGE_CURVE('E369',#327,#991,#989,.T.);
#993=ORIENTED_EDGE('',*,*,#992,.T.);
#994=DIRECTION('',(-2.99149449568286E-09,0.,1.));
#995=VECTOR('',#994,1.);
#996=CARTESIAN_POINT('',(9.99999982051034,26.,60.0000000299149));
#997=LINE('',#996,#995);
#998=EDGE_CURVE('E240',#966,#991,#997,.T.);
#999=ORIENTED_EDGE('',*,*,#998,.F.);
#1000=ORIENTED_EDGE('',*,*,#967,.T.);
#1001=EDGE_LOOP('',(#985,#993,#999,#1000));
#1002=FACE_BOUND('',#1001,.T.);
#1003=ADVANCED_FACE('F554',(#1002),#984,.F.);
#1004=CARTESIAN_POINT('',(0.,26.,0.));
#1005=DIRECTION('',(0.,1.,0.));
#1006=DIRECTION('',(2.99149428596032E-09,0.,-1.));
#1007=AXIS2_PLACEMENT_3D('',#1004,#1005,#1006);
#1008=PLANE('',#1007);
#1009=CARTESIAN_POINT('',(-1.79489657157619E-07,26.,60.));
#1010=DIRECTION('',(0.,1.,0.));
#1011=DIRECTION('',(0.,0.,1.));
#1012=AXIS2_PLACEMENT_3D('',#1009,#1010,#1011);
#1013=CIRCLE('',#1012,6.);
#1014=CARTESIAN_POINT('',(-1.79489657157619E-07,26.,66.));
#1015=VERTEX_POINT('',#1014);
#1016=EDGE_CURVE('E675',#1015,#1015,#1013,.F.);
#1017=ORIENTED_EDGE('',*,*,#1016,.F.);
#1018=EDGE_LOOP('',(#1017));
#1019=FACE_BOUND('',#1018,.T.);
#1020=ORIENTED_EDGE('',*,*,#148,.F.);
#1021=CARTESIAN_POINT('',(-13.0000001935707,26.,64.7070320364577));
#1022=DIRECTION('',(0.,1.,0.));
#1023=DIRECTION('',(0.,0.,1.));
#1024=AXIS2_PLACEMENT_3D('',#1021,#1022,#1023);
#1025=CIRCLE('',#1024,3.);
#1026=EDGE_CURVE('E372',#138,#934,#1025,.T.);
#1027=ORIENTED_EDGE('',*,*,#1026,.T.);
#1028=ORIENTED_EDGE('',*,*,#937,.T.);
#1029=ORIENTED_EDGE('',*,*,#974,.T.);
#1030=ORIENTED_EDGE('',*,*,#998,.T.);
#1031=CARTESIAN_POINT('',(12.9999998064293,26.,64.7070321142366));
#1032=DIRECTION('',(0.,1.,0.));
#1033=DIRECTION('',(0.,0.,1.));
#1034=AXIS2_PLACEMENT_3D('',#1031,#1032,#1033);
#1035=CIRCLE('',#1034,3.);
#1036=EDGE_CURVE('E377',#991,#147,#1035,.T.);
#1037=ORIENTED_EDGE('',*,*,#1036,.T.);
#1038=EDGE_LOOP('',(#1020,#1027,#1028,#1029,#1030,#1037));
#1039=FACE_BOUND('',#1038,.T.);
#1040=ADVANCED_FACE('F550',(#1019,#1039),#1008,.F.);
#1041=CARTESIAN_POINT('',(68.2715167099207,26.,10.0000003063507));
#1042=DIRECTION('',(4.48724077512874E-09,0.,-1.));
#1043=DIRECTION('',(-1.,0.,-4.48724077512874E-09));
#1044=AXIS2_PLACEMENT_3D('',#1041,#1042,#1043);
#1045=PLANE('',#1044);
#1046=DIRECTION('',(-1.,0.,-4.48724077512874E-09));
#1047=VECTOR('',#1046,1.);
#1048=CARTESIAN_POINT('',(68.2715167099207,26.,10.0000003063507));
#1049=LINE('',#1048,#1047);
#1050=CARTESIAN_POINT('',(64.7070320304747,26.,10.000000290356));
#1051=VERTEX_POINT('',#1050);
#1052=CARTESIAN_POINT('',(59.9999999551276,26.,10.0000002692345));
#1053=VERTEX_POINT('',#1052);
#1054=EDGE_CURVE('E206',#1051,#1053,#1049,.T.);
#1055=ORIENTED_EDGE('',*,*,#1054,.F.);
#1056=DIRECTION('',(0.,-1.,0.));
#1057=VECTOR('',#1056,1.);
#1058=CARTESIAN_POINT('',(64.7070320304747,26.,10.000000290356));
#1059=LINE('',#1058,#1057);
#1060=EDGE_CURVE('E382',#1051,#310,#1059,.F.);
#1061=ORIENTED_EDGE('',*,*,#1060,.T.);
#1062=ORIENTED_EDGE('',*,*,#311,.T.);
#1063=DIRECTION('',(0.,1.,0.));
#1064=VECTOR('',#1063,1.);
#1065=CARTESIAN_POINT('',(59.9999999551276,26.,10.0000002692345));
#1066=LINE('',#1065,#1064);
#1067=EDGE_CURVE('E216',#1053,#302,#1066,.T.);
#1068=ORIENTED_EDGE('',*,*,#1067,.F.);
#1069=EDGE_LOOP('',(#1055,#1061,#1062,#1068));
#1070=FACE_BOUND('',#1069,.T.);
#1071=ADVANCED_FACE('F496',(#1070),#1045,.F.);
#1072=CARTESIAN_POINT('',(60.,26.,2.69234459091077E-07));
#1073=DIRECTION('',(0.,1.,0.));
#1074=DIRECTION('',(0.,0.,1.));
#1075=AXIS2_PLACEMENT_3D('',#1072,#1073,#1074);
#1076=CYLINDRICAL_SURFACE('',#1075,10.);
#1077=ORIENTED_EDGE('',*,*,#303,.T.);
#1078=DIRECTION('',(0.,1.,0.));
#1079=VECTOR('',#1078,1.);
#1080=CARTESIAN_POINT('',(60.0000000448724,26.,-9.99999973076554));
#1081=LINE('',#1080,#1079);
#1082=CARTESIAN_POINT('',(60.0000000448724,26.,-9.99999973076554));
#1083=VERTEX_POINT('',#1082);
#1084=EDGE_CURVE('E213',#1083,#293,#1081,.T.);
#1085=ORIENTED_EDGE('',*,*,#1084,.F.);
#1086=CARTESIAN_POINT('',(60.,26.,2.69234459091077E-07));
#1087=DIRECTION('',(0.,-1.,0.));
#1088=DIRECTION('',(1.,0.,4.48724098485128E-09));
#1089=AXIS2_PLACEMENT_3D('',#1086,#1087,#1088);
#1090=CIRCLE('',#1089,10.);
#1091=EDGE_CURVE('E203',#1053,#1083,#1090,.T.);
#1092=ORIENTED_EDGE('',*,*,#1091,.F.);
#1093=ORIENTED_EDGE('',*,*,#1067,.T.);
#1094=EDGE_LOOP('',(#1077,#1085,#1092,#1093));
#1095=FACE_BOUND('',#1094,.T.);
#1096=ADVANCED_FACE('F215',(#1095),#1076,.T.);
#1097=CARTESIAN_POINT('',(60.0000000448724,26.,-9.99999973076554));
#1098=DIRECTION('',(-4.48724119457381E-09,0.,1.));
#1099=DIRECTION('',(1.,0.,4.48724119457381E-09));
#1100=AXIS2_PLACEMENT_3D('',#1097,#1098,#1099);
#1101=PLANE('',#1100);
#1102=ORIENTED_EDGE('',*,*,#294,.T.);
#1103=DIRECTION('',(0.,-1.,0.));
#1104=VECTOR('',#1103,1.);
#1105=CARTESIAN_POINT('',(64.7070321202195,26.,-9.99999970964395));
#1106=LINE('',#1105,#1104);
#1107=CARTESIAN_POINT('',(64.7070321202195,26.,-9.99999970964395));
#1108=VERTEX_POINT('',#1107);
#1109=EDGE_CURVE('E53',#285,#1108,#1106,.T.);
#1110=ORIENTED_EDGE('',*,*,#1109,.T.);
#1111=DIRECTION('',(1.,0.,4.48724119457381E-09));
#1112=VECTOR('',#1111,1.);
#1113=CARTESIAN_POINT('',(60.0000000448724,26.,-9.99999973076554));
#1114=LINE('',#1113,#1112);
#1115=EDGE_CURVE('E202',#1083,#1108,#1114,.T.);
#1116=ORIENTED_EDGE('',*,*,#1115,.F.);
#1117=ORIENTED_EDGE('',*,*,#1084,.T.);
#1118=EDGE_LOOP('',(#1102,#1110,#1116,#1117));
#1119=FACE_BOUND('',#1118,.T.);
#1120=ADVANCED_FACE('F217',(#1119),#1101,.F.);
#1121=CARTESIAN_POINT('',(0.,26.,0.));
#1122=DIRECTION('',(0.,1.,0.));
#1123=DIRECTION('',(-1.,0.,-4.48724098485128E-09));
#1124=AXIS2_PLACEMENT_3D('',#1121,#1122,#1123);
#1125=PLANE('',#1124);
#1126=CARTESIAN_POINT('',(60.,26.,2.69234459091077E-07));
#1127=DIRECTION('',(0.,1.,0.));
#1128=DIRECTION('',(0.,0.,1.));
#1129=AXIS2_PLACEMENT_3D('',#1126,#1127,#1128);
#1130=CIRCLE('',#1129,6.);
#1131=CARTESIAN_POINT('',(60.,26.,6.00000026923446));
#1132=VERTEX_POINT('',#1131);
#1133=EDGE_CURVE('E666',#1132,#1132,#1130,.F.);
#1134=ORIENTED_EDGE('',*,*,#1133,.F.);
#1135=EDGE_LOOP('',(#1134));
#1136=FACE_BOUND('',#1135,.T.);
#1137=ORIENTED_EDGE('',*,*,#61,.F.);
#1138=CARTESIAN_POINT('',(64.707032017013,26.,13.000000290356));
#1139=DIRECTION('',(0.,1.,0.));
#1140=DIRECTION('',(0.,0.,1.));
#1141=AXIS2_PLACEMENT_3D('',#1138,#1139,#1140);
#1142=CIRCLE('',#1141,3.);
#1143=EDGE_CURVE('E395',#51,#1051,#1142,.T.);
#1144=ORIENTED_EDGE('',*,*,#1143,.T.);
#1145=ORIENTED_EDGE('',*,*,#1054,.T.);
#1146=ORIENTED_EDGE('',*,*,#1091,.T.);
#1147=ORIENTED_EDGE('',*,*,#1115,.T.);
#1148=CARTESIAN_POINT('',(64.7070321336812,26.,-12.999999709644));
#1149=DIRECTION('',(0.,1.,0.));
#1150=DIRECTION('',(0.,0.,1.));
#1151=AXIS2_PLACEMENT_3D('',#1148,#1149,#1150);
#1152=CIRCLE('',#1151,3.);
#1153=EDGE_CURVE('E398',#1108,#60,#1152,.T.);
#1154=ORIENTED_EDGE('',*,*,#1153,.T.);
#1155=EDGE_LOOP('',(#1137,#1144,#1145,#1146,#1147,#1154));
#1156=FACE_BOUND('',#1155,.T.);
#1157=ADVANCED_FACE('F201',(#1136,#1156),#1125,.F.);
#1158=CARTESIAN_POINT('',(-60.,-0.001000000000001,-8.97448285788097E-08));
#1159=DIRECTION('',(0.,1.,0.));
#1160=DIRECTION('',(0.,0.,1.));
#1161=AXIS2_PLACEMENT_3D('',#1158,#1159,#1160);
#1162=CYLINDRICAL_SURFACE('',#1161,6.);
#1163=ORIENTED_EDGE('',*,*,#221,.T.);
#1164=EDGE_LOOP('',(#1163));
#1165=FACE_BOUND('',#1164,.T.);
#1166=ORIENTED_EDGE('',*,*,#899,.T.);
#1167=EDGE_LOOP('',(#1166));
#1168=FACE_BOUND('',#1167,.T.);
#1169=ADVANCED_FACE('F677',(#1165,#1168),#1162,.F.);
#1170=CARTESIAN_POINT('',(-1.79489657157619E-07,-0.001000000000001,60.));
#1171=DIRECTION('',(0.,1.,0.));
#1172=DIRECTION('',(0.,0.,1.));
#1173=AXIS2_PLACEMENT_3D('',#1170,#1171,#1172);
#1174=CYLINDRICAL_SURFACE('',#1173,6.);
#1175=ORIENTED_EDGE('',*,*,#210,.T.);
#1176=EDGE_LOOP('',(#1175));
#1177=FACE_BOUND('',#1176,.T.);
#1178=ORIENTED_EDGE('',*,*,#1016,.T.);
#1179=EDGE_LOOP('',(#1178));
#1180=FACE_BOUND('',#1179,.T.);
#1181=ADVANCED_FACE('F682',(#1177,#1180),#1174,.F.);
#1182=CARTESIAN_POINT('',(60.,-0.001000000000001,2.69234459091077E-07));
#1183=DIRECTION('',(0.,1.,0.));
#1184=DIRECTION('',(0.,0.,1.));
#1185=AXIS2_PLACEMENT_3D('',#1182,#1183,#1184);
#1186=CYLINDRICAL_SURFACE('',#1185,6.);
#1187=ORIENTED_EDGE('',*,*,#199,.T.);
#1188=EDGE_LOOP('',(#1187));
#1189=FACE_BOUND('',#1188,.T.);
#1190=ORIENTED_EDGE('',*,*,#1133,.T.);
#1191=EDGE_LOOP('',(#1190));
#1192=FACE_BOUND('',#1191,.T.);
#1193=ADVANCED_FACE('F456',(#1189,#1192),#1186,.F.);
#1194=CARTESIAN_POINT('',(-64.7070320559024,32.,-13.0000000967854));
#1195=DIRECTION('',(0.,-1.,0.));
#1196=DIRECTION('',(0.,0.,-1.));
#1197=AXIS2_PLACEMENT_3D('',#1194,#1195,#1196);
#1198=CYLINDRICAL_SURFACE('',#1197,3.);
#1199=ORIENTED_EDGE('',*,*,#909,.F.);
#1200=ORIENTED_EDGE('',*,*,#110,.F.);
#1201=ORIENTED_EDGE('',*,*,#402,.F.);
#1202=ORIENTED_EDGE('',*,*,#826,.F.);
#1203=EDGE_LOOP('',(#1199,#1200,#1201,#1202));
#1204=FACE_BOUND('',#1203,.T.);
#1205=ADVANCED_FACE('F455',(#1204),#1198,.F.);
#1206=CARTESIAN_POINT('',(-64.7070320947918,32.,12.9999999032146));
#1207=DIRECTION('',(0.,-1.,0.));
#1208=DIRECTION('',(0.,0.,-1.));
#1209=AXIS2_PLACEMENT_3D('',#1206,#1207,#1208);
#1210=CYLINDRICAL_SURFACE('',#1209,3.);
#1211=ORIENTED_EDGE('',*,*,#919,.F.);
#1212=ORIENTED_EDGE('',*,*,#875,.F.);
#1213=ORIENTED_EDGE('',*,*,#370,.F.);
#1214=ORIENTED_EDGE('',*,*,#127,.F.);
#1215=EDGE_LOOP('',(#1211,#1212,#1213,#1214));
#1216=FACE_BOUND('',#1215,.T.);
#1217=ADVANCED_FACE('F460',(#1216),#1210,.F.);
#1218=CARTESIAN_POINT('',(-13.0000001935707,32.,64.7070320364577));
#1219=DIRECTION('',(0.,-1.,0.));
#1220=DIRECTION('',(0.,0.,-1.));
#1221=AXIS2_PLACEMENT_3D('',#1218,#1219,#1220);
#1222=CYLINDRICAL_SURFACE('',#1221,3.);
#1223=ORIENTED_EDGE('',*,*,#1026,.F.);
#1224=ORIENTED_EDGE('',*,*,#139,.F.);
#1225=ORIENTED_EDGE('',*,*,#360,.F.);
#1226=ORIENTED_EDGE('',*,*,#943,.F.);
#1227=EDGE_LOOP('',(#1223,#1224,#1225,#1226));
#1228=FACE_BOUND('',#1227,.T.);
#1229=ADVANCED_FACE('F461',(#1228),#1222,.F.);
#1230=CARTESIAN_POINT('',(12.9999998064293,32.,64.7070321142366));
#1231=DIRECTION('',(0.,-1.,0.));
#1232=DIRECTION('',(0.,0.,-1.));
#1233=AXIS2_PLACEMENT_3D('',#1230,#1231,#1232);
#1234=CYLINDRICAL_SURFACE('',#1233,3.);
#1235=ORIENTED_EDGE('',*,*,#1036,.F.);
#1236=ORIENTED_EDGE('',*,*,#992,.F.);
#1237=ORIENTED_EDGE('',*,*,#328,.F.);
#1238=ORIENTED_EDGE('',*,*,#154,.F.);
#1239=EDGE_LOOP('',(#1235,#1236,#1237,#1238));
#1240=FACE_BOUND('',#1239,.T.);
#1241=ADVANCED_FACE('F470',(#1240),#1234,.F.);
#1242=CARTESIAN_POINT('',(64.707032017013,32.,13.000000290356));
#1243=DIRECTION('',(0.,-1.,0.));
#1244=DIRECTION('',(0.,0.,-1.));
#1245=AXIS2_PLACEMENT_3D('',#1242,#1243,#1244);
#1246=CYLINDRICAL_SURFACE('',#1245,3.);
#1247=ORIENTED_EDGE('',*,*,#1143,.F.);
#1248=ORIENTED_EDGE('',*,*,#52,.F.);
#1249=ORIENTED_EDGE('',*,*,#318,.F.);
#1250=ORIENTED_EDGE('',*,*,#1060,.F.);
#1251=EDGE_LOOP('',(#1247,#1248,#1249,#1250));
#1252=FACE_BOUND('',#1251,.T.);
#1253=ADVANCED_FACE('F471',(#1252),#1246,.F.);
#1254=CARTESIAN_POINT('',(64.7070321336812,32.,-12.999999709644));
#1255=DIRECTION('',(0.,-1.,0.));
#1256=DIRECTION('',(0.,0.,-1.));
#1257=AXIS2_PLACEMENT_3D('',#1254,#1255,#1256);
#1258=CYLINDRICAL_SURFACE('',#1257,3.);
#1259=ORIENTED_EDGE('',*,*,#1153,.F.);
#1260=ORIENTED_EDGE('',*,*,#1109,.F.);
#1261=ORIENTED_EDGE('',*,*,#286,.F.);
#1262=ORIENTED_EDGE('',*,*,#69,.F.);
#1263=EDGE_LOOP('',(#1259,#1260,#1261,#1262));
#1264=FACE_BOUND('',#1263,.T.);
#1265=ADVANCED_FACE('F475',(#1264),#1258,.F.);
#1266=CARTESIAN_POINT('',(0.,0.,-60.));
#1267=DIRECTION('',(0.,1.,0.));
#1268=DIRECTION('',(0.,0.,1.));
#1269=AXIS2_PLACEMENT_3D('',#1266,#1267,#1268);
#1270=CYLINDRICAL_SURFACE('',#1269,6.);
#1271=ORIENTED_EDGE('',*,*,#499,.F.);
#1272=EDGE_LOOP('',(#1271));
#1273=FACE_BOUND('',#1272,.T.);
#1274=ORIENTED_EDGE('',*,*,#629,.T.);
#1275=EDGE_LOOP('',(#1274));
#1276=FACE_BOUND('',#1275,.T.);
#1277=ADVANCED_FACE('F476',(#1273,#1276),#1270,.F.);
#1278=CARTESIAN_POINT('',(42.4264068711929,0.,-42.4264068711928));
#1279=DIRECTION('',(0.,1.,0.));
#1280=DIRECTION('',(0.,0.,1.));
#1281=AXIS2_PLACEMENT_3D('',#1278,#1279,#1280);
#1282=CYLINDRICAL_SURFACE('',#1281,6.);
#1283=ORIENTED_EDGE('',*,*,#488,.F.);
#1284=EDGE_LOOP('',(#1283));
#1285=FACE_BOUND('',#1284,.T.);
#1286=ORIENTED_EDGE('',*,*,#618,.T.);
#1287=EDGE_LOOP('',(#1286));
#1288=FACE_BOUND('',#1287,.T.);
#1289=ADVANCED_FACE('F485',(#1285,#1288),#1282,.F.);
#1290=CARTESIAN_POINT('',(60.,0.,2.09488880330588E-13));
#1291=DIRECTION('',(0.,1.,0.));
#1292=DIRECTION('',(0.,0.,1.));
#1293=AXIS2_PLACEMENT_3D('',#1290,#1291,#1292);
#1294=CYLINDRICAL_SURFACE('',#1293,6.);
#1295=ORIENTED_EDGE('',*,*,#477,.F.);
#1296=EDGE_LOOP('',(#1295));
#1297=FACE_BOUND('',#1296,.T.);
#1298=ORIENTED_EDGE('',*,*,#607,.T.);
#1299=EDGE_LOOP('',(#1298));
#1300=FACE_BOUND('',#1299,.T.);
#1301=ADVANCED_FACE('F768',(#1297,#1300),#1294,.F.);
#1302=CARTESIAN_POINT('',(42.4264068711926,0.,42.4264068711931));
#1303=DIRECTION('',(0.,1.,0.));
#1304=DIRECTION('',(0.,0.,1.));
#1305=AXIS2_PLACEMENT_3D('',#1302,#1303,#1304);
#1306=CYLINDRICAL_SURFACE('',#1305,6.);
#1307=ORIENTED_EDGE('',*,*,#466,.F.);
#1308=EDGE_LOOP('',(#1307));
#1309=FACE_BOUND('',#1308,.T.);
#1310=ORIENTED_EDGE('',*,*,#596,.T.);
#1311=EDGE_LOOP('',(#1310));
#1312=FACE_BOUND('',#1311,.T.);
#1313=ADVANCED_FACE('F777',(#1309,#1312),#1306,.F.);
#1314=CARTESIAN_POINT('',(-4.18977760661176E-13,0.,60.));
#1315=DIRECTION('',(0.,1.,0.));
#1316=DIRECTION('',(0.,0.,1.));
#1317=AXIS2_PLACEMENT_3D('',#1314,#1315,#1316);
#1318=CYLINDRICAL_SURFACE('',#1317,6.);
#1319=ORIENTED_EDGE('',*,*,#455,.F.);
#1320=EDGE_LOOP('',(#1319));
#1321=FACE_BOUND('',#1320,.T.);
#1322=ORIENTED_EDGE('',*,*,#585,.T.);
#1323=EDGE_LOOP('',(#1322));
#1324=FACE_BOUND('',#1323,.T.);
#1325=ADVANCED_FACE('F783',(#1321,#1324),#1318,.F.);
#1326=CARTESIAN_POINT('',(-42.4264068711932,0.,42.4264068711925));
#1327=DIRECTION('',(0.,1.,0.));
#1328=DIRECTION('',(0.,0.,1.));
#1329=AXIS2_PLACEMENT_3D('',#1326,#1327,#1328);
#1330=CYLINDRICAL_SURFACE('',#1329,6.);
#1331=ORIENTED_EDGE('',*,*,#444,.F.);
#1332=EDGE_LOOP('',(#1331));
#1333=FACE_BOUND('',#1332,.T.);
#1334=ORIENTED_EDGE('',*,*,#574,.T.);
#1335=EDGE_LOOP('',(#1334));
#1336=FACE_BOUND('',#1335,.T.);
#1337=ADVANCED_FACE('F791',(#1333,#1336),#1330,.F.);
#1338=CARTESIAN_POINT('',(-60.,0.,-6.28466640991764E-13));
#1339=DIRECTION('',(0.,1.,0.));
#1340=DIRECTION('',(0.,0.,1.));
#1341=AXIS2_PLACEMENT_3D('',#1338,#1339,#1340);
#1342=CYLINDRICAL_SURFACE('',#1341,6.);
#1343=ORIENTED_EDGE('',*,*,#433,.F.);
#1344=EDGE_LOOP('',(#1343));
#1345=FACE_BOUND('',#1344,.T.);
#1346=ORIENTED_EDGE('',*,*,#563,.T.);
#1347=EDGE_LOOP('',(#1346));
#1348=FACE_BOUND('',#1347,.T.);
#1349=ADVANCED_FACE('F803',(#1345,#1348),#1342,.F.);
#1350=CARTESIAN_POINT('',(-42.4264068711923,0.,-42.4264068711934));
#1351=DIRECTION('',(0.,1.,0.));
#1352=DIRECTION('',(0.,0.,1.));
#1353=AXIS2_PLACEMENT_3D('',#1350,#1351,#1352);
#1354=CYLINDRICAL_SURFACE('',#1353,6.);
#1355=ORIENTED_EDGE('',*,*,#422,.F.);
#1356=EDGE_LOOP('',(#1355));
#1357=FACE_BOUND('',#1356,.T.);
#1358=ORIENTED_EDGE('',*,*,#552,.T.);
#1359=EDGE_LOOP('',(#1358));
#1360=FACE_BOUND('',#1359,.T.);
#1361=ADVANCED_FACE('F415',(#1357,#1360),#1354,.F.);
#1362=CARTESIAN_POINT('',(0.,4.,0.));
#1363=DIRECTION('',(0.,1.,0.));
#1364=DIRECTION('',(0.,0.,1.));
#1365=AXIS2_PLACEMENT_3D('',#1362,#1363,#1364);
#1366=TOROIDAL_SURFACE('',#1365,44.5,2.);
#1367=ORIENTED_EDGE('',*,*,#530,.F.);
#1368=EDGE_LOOP('',(#1367));
#1369=FACE_BOUND('',#1368,.T.);
#1370=ORIENTED_EDGE('',*,*,#646,.F.);
#1371=EDGE_LOOP('',(#1370));
#1372=FACE_BOUND('',#1371,.T.);
#1373=ADVANCED_FACE('F408',(#1369,#1372),#1366,.T.);
#1374=CARTESIAN_POINT('',(0.,8.,0.));
#1375=DIRECTION('',(0.,1.,0.));
#1376=DIRECTION('',(0.,0.,1.));
#1377=AXIS2_PLACEMENT_3D('',#1374,#1375,#1376);
#1378=TOROIDAL_SURFACE('',#1377,67.,2.);
#1379=ORIENTED_EDGE('',*,*,#31,.F.);
#1380=EDGE_LOOP('',(#1379));
#1381=FACE_BOUND('',#1380,.T.);
#1382=ORIENTED_EDGE('',*,*,#541,.F.);
#1383=EDGE_LOOP('',(#1382));
#1384=FACE_BOUND('',#1383,.T.);
#1385=ADVANCED_FACE('F41',(#1381,#1384),#1378,.F.);
#1386=CLOSED_SHELL('',(#158,#186,#409,#517,#633,#653,#684,#709,#733,#770,#782,#794,#806,#837,
#862,#886,#923,#954,#979,#1003,#1040,#1071,#1096,#1120,#1157,#1169,#1181,#1193,#1205,#1217,
#1229,#1241,#1253,#1265,#1277,#1289,#1301,#1313,#1325,#1337,#1349,#1361,#1373,#1385));
#1387=MANIFOLD_SOLID_BREP('B2',#1386);
#1388=ADVANCED_BREP_SHAPE_REPRESENTATION('',(#18,#1387),#14);
#1389=SHAPE_DEFINITION_REPRESENTATION(#9,#1388);
ENDSEC;
END-ISO-10303-21;
